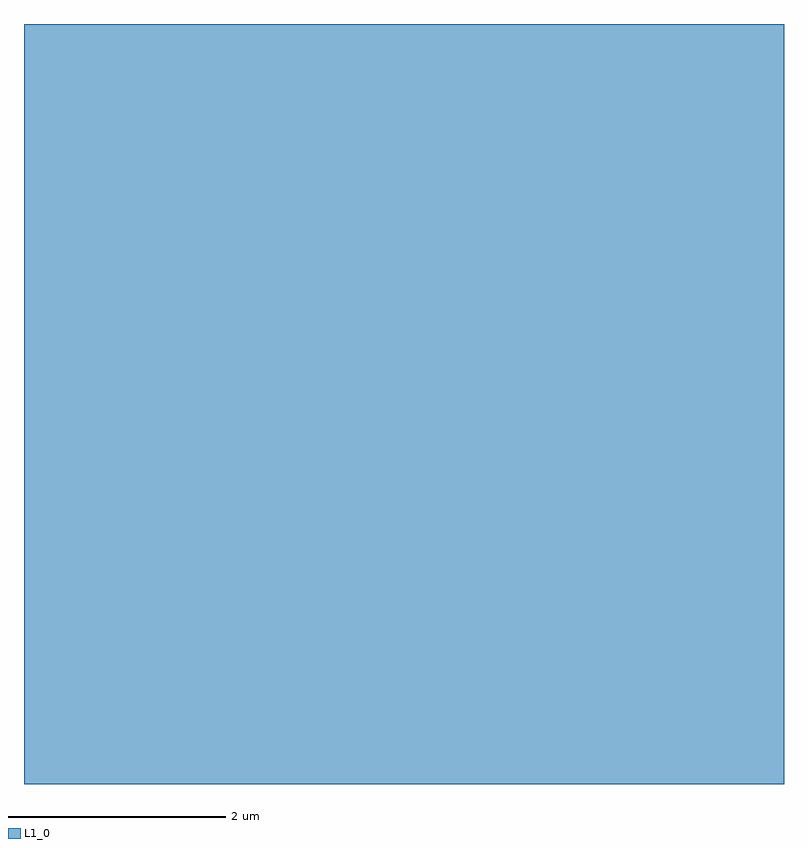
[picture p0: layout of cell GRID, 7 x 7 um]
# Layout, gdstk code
import gdstk
lib = gdstk.Library(unit=1e-6, precision=1e-09)
def R(c, l, rs):  # rectangles x0, y0, x1, y1
    for r in rs: c.add(gdstk.rectangle(r[:2], r[2:], *l))
L1_0 = (1, 0)

cell = lib.new_cell('CELL')
R(cell, L1_0, [(0,0,1,1)])

grid = lib.new_cell('GRID')
grid.add(gdstk.Reference(cell, (0,6)))
grid.add(gdstk.Reference(cell, (0,5)))
grid.add(gdstk.Reference(cell, (0,4)))
grid.add(gdstk.Reference(cell, (0,3)))
grid.add(gdstk.Reference(cell, (0,2)))
grid.add(gdstk.Reference(cell, (0,1)))
grid.add(gdstk.Reference(cell, (0,0)))
grid.add(gdstk.Reference(cell, (1,6)))
grid.add(gdstk.Reference(cell, (1,5)))
grid.add(gdstk.Reference(cell, (1,4)))
grid.add(gdstk.Reference(cell, (1,3)))
grid.add(gdstk.Reference(cell, (1,2)))
grid.add(gdstk.Reference(cell, (1,1)))
grid.add(gdstk.Reference(cell, (1,0)))
grid.add(gdstk.Reference(cell, (2,6)))
grid.add(gdstk.Reference(cell, (2,5)))
grid.add(gdstk.Reference(cell, (2,4)))
grid.add(gdstk.Reference(cell, (2,3)))
grid.add(gdstk.Reference(cell, (2,2)))
grid.add(gdstk.Reference(cell, (2,1)))
grid.add(gdstk.Reference(cell, (2,0)))
grid.add(gdstk.Reference(cell, (3,6)))
grid.add(gdstk.Reference(cell, (3,5)))
grid.add(gdstk.Reference(cell, (3,4)))
grid.add(gdstk.Reference(cell, (3,3)))
grid.add(gdstk.Reference(cell, (3,2)))
grid.add(gdstk.Reference(cell, (3,1)))
grid.add(gdstk.Reference(cell, (3,0)))
grid.add(gdstk.Reference(cell, (4,6)))
grid.add(gdstk.Reference(cell, (4,5)))
grid.add(gdstk.Reference(cell, (4,4)))
grid.add(gdstk.Reference(cell, (4,3)))
grid.add(gdstk.Reference(cell, (4,2)))
grid.add(gdstk.Reference(cell, (4,1)))
grid.add(gdstk.Reference(cell, (4,0)))
grid.add(gdstk.Reference(cell, (5,6)))
grid.add(gdstk.Reference(cell, (5,5)))
grid.add(gdstk.Reference(cell, (5,4)))
grid.add(gdstk.Reference(cell, (5,3)))
grid.add(gdstk.Reference(cell, (5,2)))
grid.add(gdstk.Reference(cell, (5,1)))
grid.add(gdstk.Reference(cell, (5,0)))
grid.add(gdstk.Reference(cell, (6,6)))
grid.add(gdstk.Reference(cell, (6,5)))
grid.add(gdstk.Reference(cell, (6,4)))
grid.add(gdstk.Reference(cell, (6,3)))
grid.add(gdstk.Reference(cell, (6,2)))
grid.add(gdstk.Reference(cell, (6,1)))
grid.add(gdstk.Reference(cell, (6,0)))

lib.write_gds('GRID.gds')
